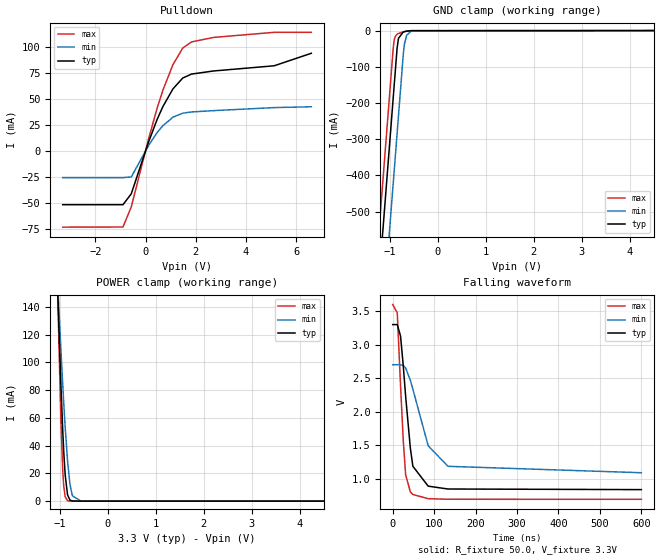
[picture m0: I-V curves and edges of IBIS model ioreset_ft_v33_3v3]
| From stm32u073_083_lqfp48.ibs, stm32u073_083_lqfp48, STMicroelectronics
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[Model]   ioreset_ft_v33_3v3
Model_type I/O_open_drain
Polarity   Inverting
Enable   Active-Low
| CAP_THRESHOLD on pad IOFT is "UDTCAPC" :
| Rising=30.0% of vddiom   Falling=70.0% of vddiom
| C_comp min and max val. don't necessarily correlate with the min and max pvt
| but are the smallest and greatest pad capacitance found.
| var   typ   min   max
C_comp   2.13775pF  2.06650pF  4.20795pF
|C_comp_pulldown   2.13775pF  2.06650pF  4.20795pF
Vinl = 1.35V
Vinh = 1.8V
Vmeas = 1.65V   | Reference voltage for timing measurements
Cref  = 50.0pF   | Timing specification test load capacitance value
Rref  = 1.0MOhm   | Timing specification test load resistance value
Vref  = 1.815V   | Timing specification test load voltage
[Model Spec]
| TIME_THRESHOLD on pin ZIV33M is "CMOS" :
| Rising=50.0% of vddiom   Falling=50.0% of vddiom
Vinl 1.34770V 1.11370V 1.44970V
Vinh 1.77530V 1.49530V 1.90330V
| variable   typ   min   max
[Temperature Range] 25.0 125.0 -40.0
| variable   typ   min   max
[Voltage Range] 3.3V 2.7V 3.6V
| variable   typ   min   max
[POWER Clamp Reference] 3.3V 2.7V 3.6V
| variable   typ   min   max
[GND Clamp Reference] 0V 0V 0V
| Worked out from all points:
|   slope of the pulldown table from 0 to 0.495 V, typ, clamps not added: 15.4 ohm
|   GND clamp passes 1 mA (typ) near -0.60 V on its own axis
|   POWER clamp passes 1 mA (typ) near -0.80 V on its own axis
|   falling waveform, R_fixture 50.0, V_fixture 3.3V: 20-80 % time 21.3ns typ, 48.5ns min, 13.6ns max; typ from 3.3 V to 0.835 V
[POWER Clamp]
-3.3V     3.015A     2.054A     3.978A
-1.06V    166.8mA    167.3mA    172.4mA
-1.05V    156mA      159.9mA    156.7mA
-980mV    85.12mA    110.1mA    59.21mA
-940mV    50.68mA    83.63mA    21.78mA
-920mV    36.19mA    71.13mA    10.91mA
-890mV    19.13mA    53.62mA    3.147mA
-840mV    4.466mA    28.97mA    309.8uA
-790mV    763.7uA    12.17mA    28.67uA
-740mV    119.7uA    3.892mA    2.636uA
-560mV    142.6nA    28.02uA    524.6pA
6.6V      0A         0A         0A
[GND Clamp]
-3.3V     -4.214A    -4.451A    -4.077A
-1.25V    -729.3mA   -965.7mA   -592.4mA
-930mV    -185.3mA   -421.7mA   -48.35mA
-910mV    -151.3mA   -387.7mA   -26.77mA
-890mV    -117.3mA   -353.7mA   -16.93mA
-850mV    -49.27mA   -285.7mA   -10.05mA
-820mV    -21.32mA   -234.7mA   -8.07mA
-720mV    -3.795mA   -64.65mA   -4.019mA
-700mV    -3.06mA    -39.82mA   -3.365mA
-650mV    -1.784mA   -12.81mA   -1.962mA
-550mV    -401.1uA   -1.592mA   -348uA
6.6V      411.3pA    9.143nA    392.1pA
| variable   typ   min   max
[Pullup Reference] 3.3V 2.7V 3.6V
| variable   typ   min   max
[Pulldown Reference] 0V 0V 0V
[Pulldown]
-3.3V     -51.64mA   -25.66mA   -73.18mA
-900mV    -51.64mA   -25.66mA   -73.04mA
-570mV    -41.2mA    -25.04mA   -53.78mA
120mV     8.582mA    5.119mA    11.54mA
460mV     30.18mA    17.52mA    41mA
690mV     42.49mA    24.14mA    58.21mA
1.09V     59.44mA    32.3mA     82.71mA
1.48V     69.88mA    36.14mA    98.63mA
1.83V     73.65mA    37.33mA    104.5mA
2.7V      76.61mA    38.58mA    108.8mA
5.12V     81.6mA     41.5mA     113.7mA
6.6V      93.6mA     42.3mA     113.7mA
[Ramp]
dV/dt_r 1.47909V/1.1362ns 967.74853mV/2.15748ns 1.74876V/824.7343ps
dV/dt_f 1.47909V/21.15643ns 967.8915mV/44.62641ns 1.74612V/13.64449ns
R_load = 50.0
| Removed startup time: 0s 0s 0s  .
| Removed end time: 599.85ns.
[Falling Waveform]
R_fixture   = 50.0
V_fixture   = 3.3V
V_fixture_min = 2.7V
V_fixture_max = 3.6V
0s        3.3V       2.7V       3.6V
11ns      3.3V       2.7V       3.475V
18.9ns    3.129V     2.7V       2.391V
25.45ns   2.685V     2.691V     1.568V
31.25ns   2.224V     2.651V     1.053V
42.6ns    1.452V     2.467V     800.7mV
48.65ns   1.184V     2.334V     762.2mV
85.6ns    886.6mV    1.49V      699.4mV
133.3ns   844mV      1.183V     690.8mV
599.9ns   834.9mV    1.087V     689.8mV
